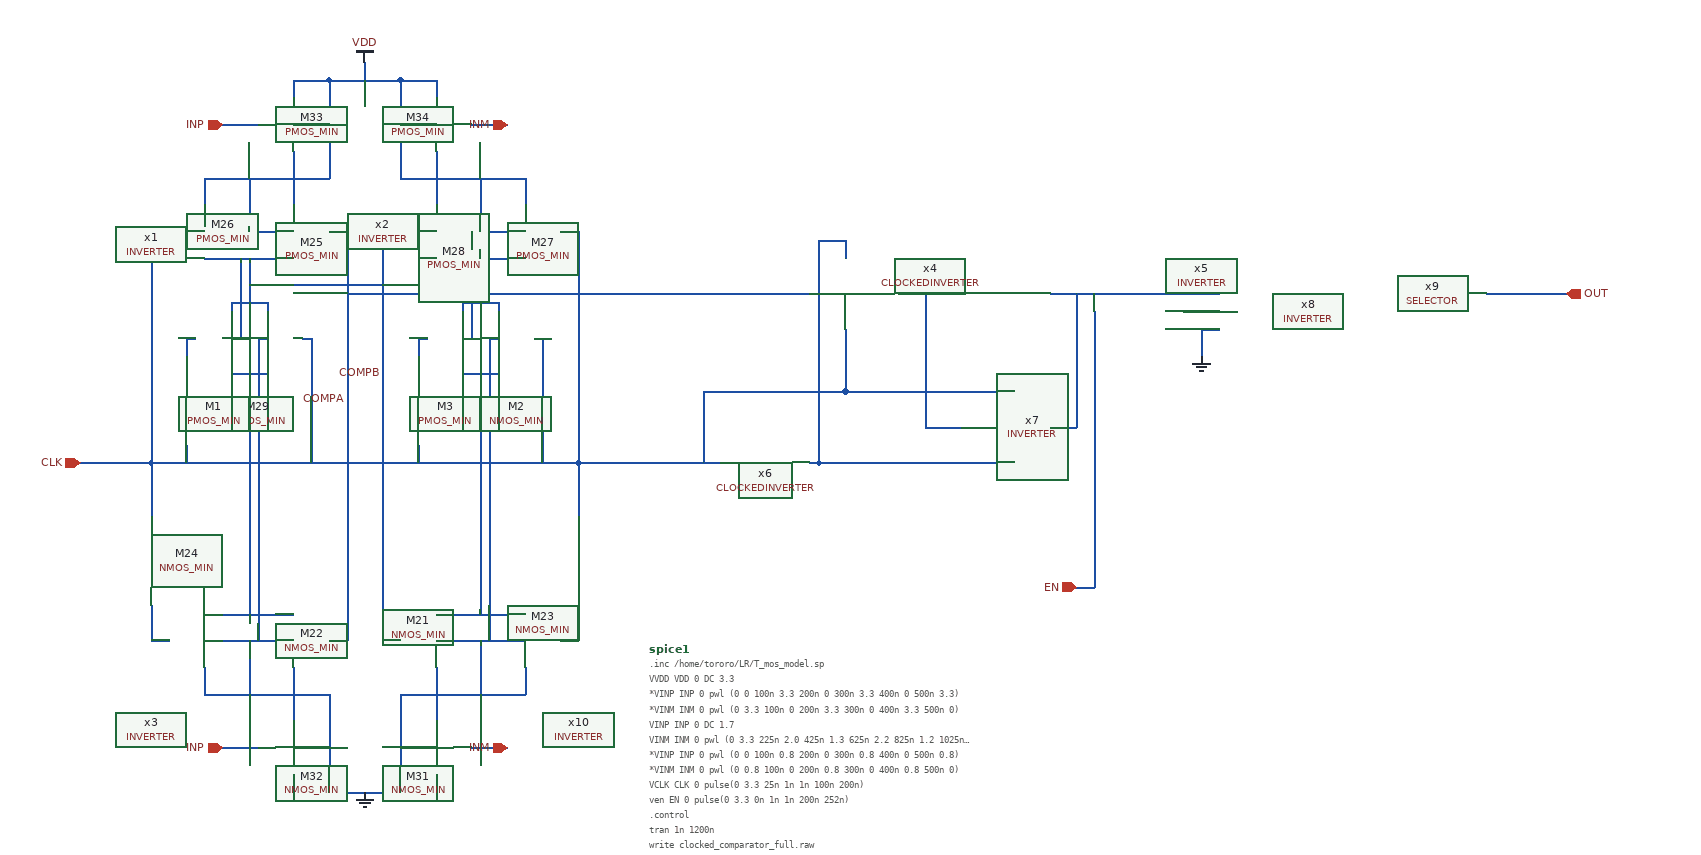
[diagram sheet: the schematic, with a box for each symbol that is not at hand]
v {xschem version=3.4.7RC file_version=1.2}
G {}
K {}
V {}
S {}
E {}
N 220 -90 220 -70 {lab=GND}
N 580 -90 580 -70 {lab=GND}
N 240 -120 320 -120 {lab=GND}
N 360 -120 380 -120 {lab=COMPA}
N 420 -120 440 -120 {lab=COMPB}
N 240 -150 320 -150 {lab=#net1}
N 620 -120 640 -120 {lab=#net2}
N 160 -120 180 -120 {lab=#net3}
N 480 -550 580 -550 {lab=COMPA}
N 220 -550 320 -550 {lab=COMPB}
N 480 -580 580 -580 {lab=VDD}
N 220 -580 320 -580 {lab=VDD}
N 270 -620 270 -580 {lab=VDD}
N 530 -620 530 -580 {lab=VDD}
N 420 -580 440 -580 {lab=COMPB}
N 360 -580 380 -580 {lab=COMPA}
N 340 50 480 50 {lab=GND}
N 480 30 480 50 {lab=GND}
N 320 30 320 50 {lab=GND}
N 320 50 340 50 {lab=GND}
N 320 0 340 0 {lab=GND}
N 460 0 480 0 {lab=GND}
N 240 0 280 0 {lab=INP}
N 520 0 560 0 {lab=INM}
N 240 -700 280 -700 {lab=INP}
N 520 -700 560 -700 {lab=INM}
N 440 -700 480 -700 {lab=VDD}
N 320 -700 360 -700 {lab=VDD}
N 320 -90 320 -30 {lab=#net4}
N 480 -90 480 -30 {lab=#net5}
N 320 -670 320 -610 {lab=#net6}
N 480 -670 480 -610 {lab=#net7}
N 220 -640 360 -640 {lab=VDD}
N 360 -750 360 -640 {lab=VDD}
N 220 -640 220 -610 {lab=VDD}
N 270 -640 270 -620 {lab=VDD}
N 580 -640 580 -620 {lab=VDD}
N 440 -640 580 -640 {lab=VDD}
N 440 -750 440 -640 {lab=VDD}
N 530 -640 530 -620 {lab=VDD}
N 360 -750 440 -750 {lab=VDD}
N 400 -770 400 -750 {lab=VDD}
N 320 -750 320 -730 {lab=VDD}
N 320 -750 360 -750 {lab=VDD}
N 480 -750 480 -730 {lab=VDD}
N 440 -750 480 -750 {lab=VDD}
N 580 -70 580 -60 {lab=GND}
N 440 -60 440 50 {lab=GND}
N 440 0 460 0 {lab=GND}
N 240 -60 360 -60 {lab=GND}
N 220 -70 220 -60 {lab=GND}
N 360 -60 360 50 {lab=GND}
N 340 0 360 0 {lab=GND}
N 220 -150 240 -150 {lab=#net1}
N 480 -150 580 -150 {lab=#net8}
N 480 -120 580 -120 {lab=GND}
N 440 -60 580 -60 {lab=GND}
N 530 -120 530 -60 {lab=GND}
N 220 -120 240 -120 {lab=GND}
N 220 -60 240 -60 {lab=GND}
N 270 -120 270 -60 {lab=GND}
N 380 -580 380 -220 {lab=COMPA}
N 420 -580 420 -220 {lab=COMPB}
N 360 -320 640 -320 {lab=CLK}
N 160 -320 360 -320 {lab=CLK}
N 80 -320 160 -320 {lab=CLK}
N 160 -580 180 -580 {lab=CLK}
N 620 -580 640 -580 {lab=CLK}
N 640 -580 640 -320 {lab=CLK}
N 160 -580 160 -320 {lab=CLK}
N 910 -320 1110 -320 {lab=#net9}
N 1230 -510 1250 -510 {lab=#net10}
N 1200 -510 1200 -410 {lab=#net10}
N 1250 -510 1270 -510 {lab=#net10}
N 900 -320 910 -320 {lab=#net9}
N 940 -400 1110 -400 {lab=CLK}
N 1270 -510 1340 -510 {lab=#net10}
N 1660 -510 1750 -510 {lab=OUT}
N 1340 -470 1340 -440 {lab=GND}
N 1330 -490 1340 -490 {lab=#net11}
N 1340 -510 1360 -510 {lab=#net10}
N 1340 -490 1360 -490 {lab=#net11}
N 1340 -470 1360 -470 {lab=GND}
N 770 -320 800 -320 {lab=CLK}
N 940 -570 940 -550 {lab=#net9}
N 910 -570 940 -570 {lab=#net9}
N 910 -570 910 -370 {lab=#net9}
N 800 -400 940 -400 {lab=CLK}
N 780 -400 780 -320 {lab=CLK}
N 780 -400 800 -400 {lab=CLK}
N 940 -470 940 -450 {lab=CLK}
N 1320 -490 1330 -490 {lab=#net11}
N 1220 -490 1220 -310 {lab=EN}
N 1170 -510 1230 -510 {lab=#net10}
N 1110 -320 1130 -320 {lab=#net9}
N 1110 -400 1130 -400 {lab=CLK}
N 1000 -510 1070 -510 {lab=#net12}
N 1030 -360 1070 -360 {lab=#net12}
N 700 -320 770 -320 {lab=CLK}
N 910 -370 910 -320 {lab=#net9}
N 1030 -420 1030 -360 {lab=#net12}
N 940 -450 940 -400 {lab=CLK}
N 1030 -510 1030 -420 {lab=#net12}
N 1170 -360 1200 -360 {lab=#net10}
N 1200 -410 1200 -360 {lab=#net10}
N 1220 -310 1220 -180 {lab=EN}
N 1200 -180 1220 -180 {lab=EN}
N 640 -320 700 -320 {lab=CLK}
N 250 -500 290 -500 {lab=COMPB}
N 250 -420 290 -420 {lab=#net1}
N 250 -460 260 -460 {lab=COMPB}
N 280 -460 290 -460 {lab=GND}
N 250 -500 250 -490 {lab=COMPB}
N 290 -500 290 -490 {lab=COMPB}
N 250 -430 250 -420 {lab=#net1}
N 290 -430 290 -420 {lab=#net1}
N 330 -460 340 -460 {lab=CLK}
N 270 -550 270 -500 {lab=COMPB}
N 260 -550 260 -460 {lab=COMPB}
N 200 -460 210 -460 {lab=#net13}
N 200 -460 200 -440 {lab=#net13}
N 200 -340 200 -320 {lab=CLK}
N 280 -460 280 -220 {lab=GND}
N 270 -420 270 -250 {lab=#net1}
N 510 -500 550 -500 {lab=COMPA}
N 510 -420 550 -420 {lab=#net8}
N 510 -460 520 -460 {lab=VDD}
N 540 -460 550 -460 {lab=GND}
N 510 -500 510 -490 {lab=COMPA}
N 550 -500 550 -490 {lab=COMPA}
N 510 -430 510 -420 {lab=#net8}
N 550 -430 550 -420 {lab=#net8}
N 590 -460 600 -460 {lab=CLK}
N 530 -550 530 -500 {lab=COMPA}
N 460 -460 470 -460 {lab=#net14}
N 460 -460 460 -440 {lab=#net14}
N 460 -340 460 -320 {lab=CLK}
N 540 -460 540 -220 {lab=GND}
N 530 -420 530 -250 {lab=#net8}
N 520 -580 520 -460 {lab=VDD}
N 340 -460 340 -320 {lab=CLK}
N 600 -460 600 -320 {lab=CLK}
N 580 -620 580 -610 {lab=VDD}
N 530 -510 900 -510 {lab=COMPA}
N 380 -510 530 -510 {lab=COMPA}
N 270 -520 420 -520 {lab=COMPB}
N 540 -220 540 -120 {lab=GND}
N 530 -250 530 -150 {lab=#net8}
N 270 -250 270 -150 {lab=#net1}
N 380 -220 380 -120 {lab=COMPA}
N 420 -220 420 -120 {lab=COMPB}
N 280 -220 280 -120 {lab=GND}
N 160 -320 160 -260 {lab=CLK}
N 160 -160 160 -120 {lab=#net3}
N 640 -320 640 -260 {lab=CLK}
N 640 -160 640 -120 {lab=#net2}
C {NMOS_MIN.sym} 440 -120 0 0 {name=M21 model=nch w=3.5u l=0.35u as=0 ps=0 ad=0 pd=0 m=1}
C {NMOS_MIN.sym} 360 -120 2 0 {name=M22 model=nch w=3.5u l=0.35u as=0 ps=0 ad=0 pd=0 m=1}
C {NMOS_MIN.sym} 620 -120 2 0 {name=M23 model=nch w=3.5u l=0.35u as=0 ps=0 ad=0 pd=0 m=1}
C {NMOS_MIN.sym} 180 -120 0 0 {name=M24 model=nch w=3.5u l=0.35u as=0 ps=0 ad=0 pd=0 m=1}
C {PMOS_MIN.sym} 360 -580 2 0 {name=M25 model=pch w=10.5u l=0.35u as=0 ps=0 ad=0 pd=0 m=1qqq}
C {PMOS_MIN.sym} 180 -580 0 0 {name=M26 model=pch w=10.5u l=0.35u as=0 ps=0 ad=0 pd=0 m=1}
C {PMOS_MIN.sym} 620 -580 2 0 {name=M27 model=pch w=10.5u l=0.35u as=0 ps=0 ad=0 pd=0 m=1qqq}
C {PMOS_MIN.sym} 440 -580 0 0 {name=M28 model=pch w=10.5u l=0.35u as=0 ps=0 ad=0 pd=0 m=1}
C {NMOS_MIN.sym} 330 -460 2 0 {name=M29 model=nch w=3.5u l=0.35u as=0 ps=0 ad=0 pd=0 m=1}
C {gnd.sym} 400 50 0 0 {name=l6 lab=GND}
C {NMOS_MIN.sym} 520 0 2 0 {name=M31 model=nch w=3.5u l=0.35u as=0 ps=0 ad=0 pd=0 m=1}
C {NMOS_MIN.sym} 280 0 0 0 {name=M32 model=nch w=3.5u l=0.35u as=0 ps=0 ad=0 pd=0 m=1}
C {ipin.sym} 240 0 0 0 {name=p5 lab=INP}
C {ipin.sym} 560 0 2 0 {name=p8 lab=INM}
C {PMOS_MIN.sym} 280 -700 0 0 {name=M33 model=pch w=10.5u l=0.35u as=0 ps=0 ad=0 pd=0 m=1}
C {PMOS_MIN.sym} 520 -700 2 0 {name=M34 model=pch w=10.5u l=0.35u as=0 ps=0 ad=0 pd=0 m=1qqq}
C {ipin.sym} 240 -700 0 0 {name=p9 lab=INP}
C {ipin.sym} 560 -700 2 0 {name=p10 lab=INM}
C {vdd.sym} 400 -770 0 0 {name=l7 lab=VDD}
C {ipin.sym} 80 -320 0 0 {name=p11 lab=CLK}
C {code_shown.sym} 720 -110 0 0 {name=spice1 only_toplevel=false value="

.inc /home/tororo/LR/T_mos_model.sp

VVDD VDD 0 DC 3.3

*VINP INP 0 pwl (0   0 100n 3.3 200n   0 300n 3.3 400n   0 500n 3.3)
*VINM INM 0 pwl (0 3.3 100n   0 200n 3.3 300n   0 400n 3.3 500n 0)

VINP INP 0 DC 1.7
VINM INM 0 pwl (0 3.3 225n 2.0 425n 1.3 625n 2.2 825n 1.2 1025n 1.8)

*VINP INP 0 pwl (0   0 100n 0.8 200n   0 300n 0.8 400n   0 500n 0.8)
*VINM INM 0 pwl (0 0.8 100n   0 200n 0.8 300n   0 400n 0.8 500n 0)


VCLK CLK 0 pulse(0 3.3 25n 1n 1n 100n 200n)
ven EN 0 pulse(0 3.3 0n 1n 1n 200n 252n)

.control
tran 1n 1200n

write "clocked_comparator_full.raw"

.endc"}
C {opin.sym} 1750 -510 0 0 {name=p2 lab=OUT}
C {ipin.sym} 1200 -180 0 0 {name=p3 lab=EN}
C {gnd.sym} 1340 -440 0 0 {name=l4 lab=GND}
C {lab_wire.sym} 380 -390 0 0 {name=p6 sig_type=std_logic lab=COMPA}
C {lab_wire.sym} 420 -420 0 0 {name=p7 sig_type=std_logic lab=COMPB}
C {PMOS_MIN.sym} 210 -460 0 0 {name=M1 model=pch w=10.5u l=0.35u as=0 ps=0 ad=0 pd=0 m=1}
C {LR_Work2/symbol/INVERTER.sym} 200 -580 3 0 {name=x1}
C {NMOS_MIN.sym} 590 -460 2 0 {name=M2 model=nch w=3.5u l=0.35u as=0 ps=0 ad=0 pd=0 m=1}
C {PMOS_MIN.sym} 470 -460 0 0 {name=M3 model=pch w=10.5u l=0.35u as=0 ps=0 ad=0 pd=0 m=1}
C {LR_Work2/symbol/INVERTER.sym} 460 -580 3 0 {name=x2}
C {LR_Work2/symbol/INVERTER.sym} 640 -20 1 0 {name=x10}
C {LR_Work2/symbol/INVERTER.sym} 160 -20 1 0 {name=x3}
C {LR_Work2/symbol/INVERTER.sym} 1310 -510 0 0 {name=x5}
C {LR_Work2/symbol/INVERTER.sym} 1040 -320 0 0 {name=x7}
C {LR_Work2/symbol/INVERTER.sym} 1460 -490 0 0 {name=x8}
C {LR_Work2/symbol/CLOCKEDINVERTER.sym} 1060 -510 0 0 {name=x4}
C {LR_Work2/symbol/CLOCKEDINVERTER.sym} 1010 -360 2 0 {name=x6}
C {LR_Work2/symbol/SELECTOR.sym} 1510 -490 0 0 {name=x9}
